VERSION 5.7 ;
  NOWIREEXTENSIONATPIN ON ;
  DIVIDERCHAR "/" ;
  BUSBITCHARS "[]" ;
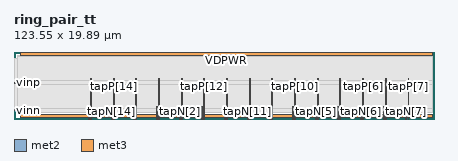
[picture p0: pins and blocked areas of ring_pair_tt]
MACRO ring_pair_tt
  CLASS BLOCK ;
  FOREIGN ring_pair_tt ;
  ORIGIN 0.000 0.000 ;
  SIZE 123.550 BY 19.890 ;
  PIN tapN[0]
    DIRECTION OUTPUT ;
    USE SIGNAL ;
    ANTENNADIFFAREA 0.365400 ;
    PORT
      LAYER met2 ;
        RECT 21.930 0.000 22.190 3.815 ;
    END
  END tapN[0]
  PIN tapP[0]
    DIRECTION OUTPUT ;
    USE SIGNAL ;
    ANTENNADIFFAREA 0.365400 ;
    PORT
      LAYER met2 ;
        RECT 22.525 0.000 22.785 11.915 ;
    END
  END tapP[0]
  PIN tapN[1]
    DIRECTION OUTPUT ;
    USE SIGNAL ;
    ANTENNADIFFAREA 0.365400 ;
    PORT
      LAYER met2 ;
        RECT 35.270 0.000 35.530 3.815 ;
    END
  END tapN[1]
  PIN tapP[1]
    DIRECTION OUTPUT ;
    USE SIGNAL ;
    ANTENNADIFFAREA 0.365400 ;
    PORT
      LAYER met2 ;
        RECT 35.865 0.000 36.125 11.915 ;
    END
  END tapP[1]
  PIN tapN[2]
    DIRECTION OUTPUT ;
    USE SIGNAL ;
    ANTENNADIFFAREA 0.365400 ;
    PORT
      LAYER met2 ;
        RECT 48.610 0.000 48.870 3.815 ;
    END
  END tapN[2]
  PIN tapP[2]
    DIRECTION OUTPUT ;
    USE SIGNAL ;
    ANTENNADIFFAREA 0.365400 ;
    PORT
      LAYER met2 ;
        RECT 49.205 0.000 49.465 11.915 ;
    END
  END tapP[2]
  PIN tapN[3]
    DIRECTION OUTPUT ;
    USE SIGNAL ;
    ANTENNADIFFAREA 0.365400 ;
    PORT
      LAYER met2 ;
        RECT 61.950 0.000 62.210 3.815 ;
    END
  END tapN[3]
  PIN tapP[3]
    DIRECTION OUTPUT ;
    USE SIGNAL ;
    ANTENNADIFFAREA 0.365400 ;
    PORT
      LAYER met2 ;
        RECT 62.545 0.000 62.805 11.915 ;
    END
  END tapP[3]
  PIN tapN[4]
    DIRECTION OUTPUT ;
    USE SIGNAL ;
    ANTENNADIFFAREA 0.365400 ;
    PORT
      LAYER met2 ;
        RECT 75.290 0.000 75.550 3.815 ;
    END
  END tapN[4]
  PIN tapP[4]
    DIRECTION OUTPUT ;
    USE SIGNAL ;
    ANTENNADIFFAREA 0.365400 ;
    PORT
      LAYER met2 ;
        RECT 75.885 0.000 76.145 11.915 ;
    END
  END tapP[4]
  PIN tapN[5]
    DIRECTION OUTPUT ;
    USE SIGNAL ;
    ANTENNADIFFAREA 0.365400 ;
    PORT
      LAYER met2 ;
        RECT 88.630 0.000 88.890 3.815 ;
    END
  END tapN[5]
  PIN tapP[5]
    DIRECTION OUTPUT ;
    USE SIGNAL ;
    ANTENNADIFFAREA 0.365400 ;
    PORT
      LAYER met2 ;
        RECT 89.225 0.000 89.485 11.915 ;
    END
  END tapP[5]
  PIN tapN[6]
    DIRECTION OUTPUT ;
    USE SIGNAL ;
    ANTENNADIFFAREA 0.365400 ;
    PORT
      LAYER met2 ;
        RECT 101.970 0.000 102.230 3.815 ;
    END
  END tapN[6]
  PIN tapP[6]
    DIRECTION OUTPUT ;
    USE SIGNAL ;
    ANTENNADIFFAREA 0.365400 ;
    PORT
      LAYER met2 ;
        RECT 102.565 0.000 102.825 11.915 ;
    END
  END tapP[6]
  PIN tapN[7]
    DIRECTION OUTPUT ;
    USE SIGNAL ;
    ANTENNADIFFAREA 0.365400 ;
    PORT
      LAYER met2 ;
        RECT 115.310 0.000 115.570 3.815 ;
    END
  END tapN[7]
  PIN tapP[7]
    DIRECTION OUTPUT ;
    USE SIGNAL ;
    ANTENNADIFFAREA 0.365400 ;
    PORT
      LAYER met2 ;
        RECT 115.905 0.000 116.165 11.915 ;
    END
  END tapP[7]
  PIN tapN[8]
    DIRECTION OUTPUT ;
    USE SIGNAL ;
    ANTENNADIFFAREA 0.365400 ;
    PORT
      LAYER met2 ;
        RECT 108.640 0.000 108.900 3.815 ;
    END
  END tapN[8]
  PIN tapP[8]
    DIRECTION OUTPUT ;
    USE SIGNAL ;
    ANTENNADIFFAREA 0.365400 ;
    PORT
      LAYER met2 ;
        RECT 109.235 0.000 109.495 11.915 ;
    END
  END tapP[8]
  PIN tapN[9]
    DIRECTION OUTPUT ;
    USE SIGNAL ;
    ANTENNADIFFAREA 0.365400 ;
    PORT
      LAYER met2 ;
        RECT 95.300 0.000 95.560 3.815 ;
    END
  END tapN[9]
  PIN tapP[9]
    DIRECTION OUTPUT ;
    USE SIGNAL ;
    ANTENNADIFFAREA 0.365400 ;
    PORT
      LAYER met2 ;
        RECT 95.895 0.000 96.155 11.915 ;
    END
  END tapP[9]
  PIN tapN[10]
    DIRECTION OUTPUT ;
    USE SIGNAL ;
    ANTENNADIFFAREA 0.365400 ;
    PORT
      LAYER met2 ;
        RECT 81.960 0.000 82.220 3.815 ;
    END
  END tapN[10]
  PIN tapP[10]
    DIRECTION OUTPUT ;
    USE SIGNAL ;
    ANTENNADIFFAREA 0.365400 ;
    PORT
      LAYER met2 ;
        RECT 82.555 0.000 82.815 11.915 ;
    END
  END tapP[10]
  PIN tapN[11]
    DIRECTION OUTPUT ;
    USE SIGNAL ;
    ANTENNADIFFAREA 0.365400 ;
    PORT
      LAYER met2 ;
        RECT 68.620 0.000 68.880 3.815 ;
    END
  END tapN[11]
  PIN tapP[11]
    DIRECTION OUTPUT ;
    USE SIGNAL ;
    ANTENNADIFFAREA 0.365400 ;
    PORT
      LAYER met2 ;
        RECT 69.215 0.000 69.475 11.915 ;
    END
  END tapP[11]
  PIN tapN[12]
    DIRECTION OUTPUT ;
    USE SIGNAL ;
    ANTENNADIFFAREA 0.365400 ;
    PORT
      LAYER met2 ;
        RECT 55.280 0.000 55.540 3.815 ;
    END
  END tapN[12]
  PIN tapP[12]
    DIRECTION OUTPUT ;
    USE SIGNAL ;
    ANTENNADIFFAREA 0.365400 ;
    PORT
      LAYER met2 ;
        RECT 55.875 0.000 56.135 11.915 ;
    END
  END tapP[12]
  PIN tapN[13]
    DIRECTION OUTPUT ;
    USE SIGNAL ;
    ANTENNADIFFAREA 0.365400 ;
    PORT
      LAYER met2 ;
        RECT 41.940 0.000 42.200 3.815 ;
    END
  END tapN[13]
  PIN tapP[13]
    DIRECTION OUTPUT ;
    USE SIGNAL ;
    ANTENNADIFFAREA 0.365400 ;
    PORT
      LAYER met2 ;
        RECT 42.535 0.000 42.795 11.915 ;
    END
  END tapP[13]
  PIN tapN[14]
    DIRECTION OUTPUT ;
    USE SIGNAL ;
    ANTENNADIFFAREA 0.365400 ;
    PORT
      LAYER met2 ;
        RECT 28.600 0.000 28.860 3.815 ;
    END
  END tapN[14]
  PIN tapP[14]
    DIRECTION OUTPUT ;
    USE SIGNAL ;
    ANTENNADIFFAREA 0.365400 ;
    PORT
      LAYER met2 ;
        RECT 29.195 0.000 29.455 11.915 ;
    END
  END tapP[14]
  PIN VGND
    DIRECTION INOUT ;
    USE GROUND ;
    PORT
      LAYER met3 ;
        RECT 2.000 0.450 123.250 1.450 ;
    END
  END VGND
  PIN VDPWR
    DIRECTION INOUT ;
    USE POWER ;
    PORT
      LAYER met3 ;
        RECT 2.000 18.685 123.250 19.685 ;
    END
  END VDPWR
  PIN vinp
    DIRECTION INPUT ;
    USE ANALOG ;
    ANTENNAGATEAREA 4.830000 ;
    PORT
      LAYER met3 ;
        RECT 0.000 10.550 1.685 10.850 ;
    END
  END vinp
  PIN vinn
    DIRECTION INPUT ;
    USE ANALOG ;
    ANTENNAGATEAREA 4.830000 ;
    PORT
      LAYER met3 ;
        RECT 0.000 2.450 1.090 2.750 ;
    END
  END vinn
  OBS
      LAYER nwell ;
        RECT 0.000 3.045 116.615 17.690 ;
      LAYER li1 ;
        RECT 0.180 3.175 116.435 17.510 ;
      LAYER met1 ;
        RECT 0.265 2.910 122.900 17.750 ;
      LAYER met2 ;
        RECT 1.070 12.195 122.900 18.285 ;
        RECT 1.070 4.095 22.245 12.195 ;
        RECT 23.065 4.095 28.915 12.195 ;
        RECT 29.735 4.095 35.585 12.195 ;
        RECT 36.405 4.095 42.255 12.195 ;
        RECT 43.075 4.095 48.925 12.195 ;
        RECT 49.745 4.095 55.595 12.195 ;
        RECT 56.415 4.095 62.265 12.195 ;
        RECT 63.085 4.095 68.935 12.195 ;
        RECT 69.755 4.095 75.605 12.195 ;
        RECT 76.425 4.095 82.275 12.195 ;
        RECT 83.095 4.095 88.945 12.195 ;
        RECT 89.765 4.095 95.615 12.195 ;
        RECT 96.435 4.095 102.285 12.195 ;
        RECT 103.105 4.095 108.955 12.195 ;
        RECT 109.775 4.095 115.625 12.195 ;
        RECT 1.070 2.415 21.650 4.095 ;
        RECT 23.065 2.415 28.320 4.095 ;
        RECT 29.735 2.415 34.990 4.095 ;
        RECT 36.405 2.415 41.660 4.095 ;
        RECT 43.075 2.415 48.330 4.095 ;
        RECT 49.745 2.415 55.000 4.095 ;
        RECT 56.415 2.415 61.670 4.095 ;
        RECT 63.085 2.415 68.340 4.095 ;
        RECT 69.755 2.415 75.010 4.095 ;
        RECT 76.425 2.415 81.680 4.095 ;
        RECT 83.095 2.415 88.350 4.095 ;
        RECT 89.765 2.415 95.020 4.095 ;
        RECT 96.435 2.415 101.690 4.095 ;
        RECT 103.105 2.415 108.360 4.095 ;
        RECT 109.775 2.415 115.030 4.095 ;
        RECT 116.445 2.415 122.900 12.195 ;
      LAYER met3 ;
        RECT 1.065 18.285 1.600 18.685 ;
        RECT 1.065 11.250 123.050 18.285 ;
        RECT 2.085 10.150 123.050 11.250 ;
        RECT 1.065 3.150 123.050 10.150 ;
        RECT 1.490 2.050 123.050 3.150 ;
        RECT 1.065 1.850 123.050 2.050 ;
        RECT 1.065 1.450 1.600 1.850 ;
  END
END ring_pair_tt
END LIBRARY

